VERSION 5.7 ;
  NOWIREEXTENSIONATPIN ON ;
  DIVIDERCHAR "/" ;
  BUSBITCHARS "[]" ;
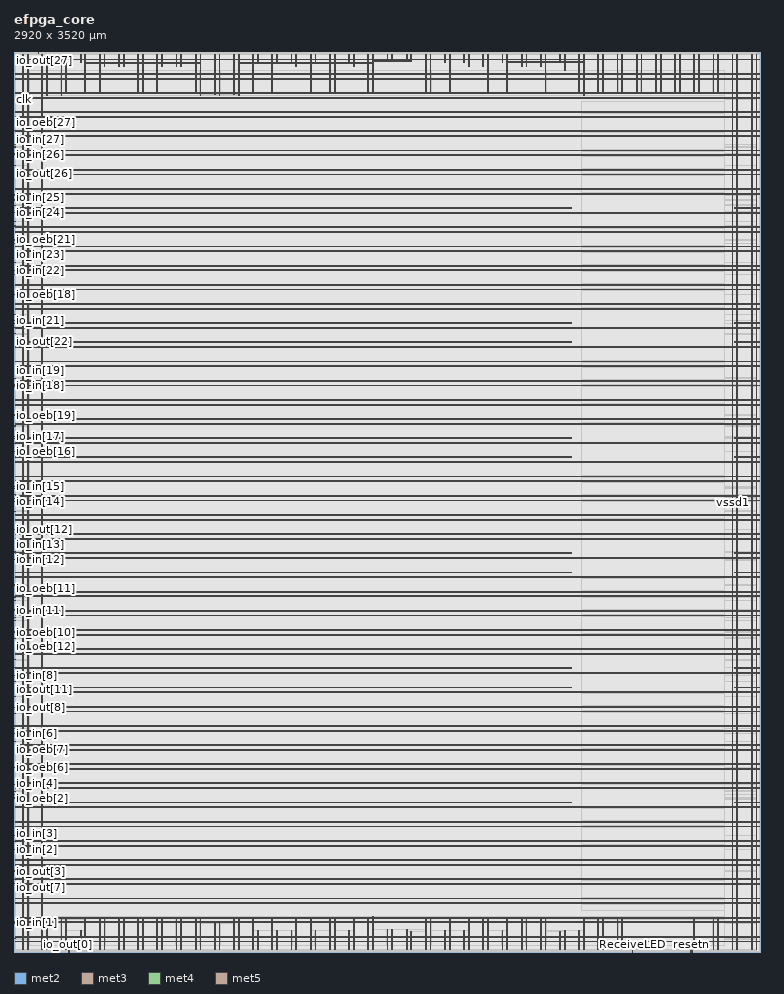
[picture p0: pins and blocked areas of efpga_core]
MACRO efpga_core
  CLASS BLOCK ;
  FOREIGN efpga_core ;
  ORIGIN 0.000 0.000 ;
  SIZE 2920.000 BY 3520.000 ;
  PIN ComActive
    DIRECTION OUTPUT ;
    USE SIGNAL ;
    ANTENNADIFFAREA 2.673000 ;
    PORT
      LAYER met2 ;
        RECT 2646.930 0.000 2647.210 4.000 ;
    END
  END ComActive
  PIN ReceiveLED
    DIRECTION OUTPUT ;
    USE SIGNAL ;
    ANTENNADIFFAREA 2.673000 ;
    PORT
      LAYER met2 ;
        RECT 2418.310 0.000 2418.590 4.000 ;
    END
  END ReceiveLED
  PIN Rx
    DIRECTION INPUT ;
    USE SIGNAL ;
    ANTENNAGATEAREA 0.196500 ;
    PORT
      LAYER met2 ;
        RECT 2653.370 0.000 2653.650 4.000 ;
    END
  END Rx
  PIN clk
    DIRECTION INPUT ;
    USE SIGNAL ;
    ANTENNAGATEAREA 0.213000 ;
    PORT
      LAYER met3 ;
        RECT 0.000 3335.440 4.000 3336.040 ;
    END
  END clk
  PIN io_in[0]
    DIRECTION INPUT ;
    USE SIGNAL ;
    ANTENNAGATEAREA 0.213000 ;
    PORT
      LAYER met3 ;
        RECT 0.000 112.240 4.000 112.840 ;
    END
  END io_in[0]
  PIN io_in[10]
    DIRECTION INPUT ;
    USE SIGNAL ;
    ANTENNAGATEAREA 0.126000 ;
    PORT
      LAYER met3 ;
        RECT 0.000 1309.040 4.000 1309.640 ;
    END
  END io_in[10]
  PIN io_in[11]
    DIRECTION INPUT ;
    USE SIGNAL ;
    ANTENNAGATEAREA 0.196500 ;
    PORT
      LAYER met3 ;
        RECT 0.000 1336.240 4.000 1336.840 ;
    END
  END io_in[11]
  PIN io_in[12]
    DIRECTION INPUT ;
    USE SIGNAL ;
    ANTENNAGATEAREA 0.126000 ;
    PORT
      LAYER met3 ;
        RECT 0.000 1533.440 4.000 1534.040 ;
    END
  END io_in[12]
  PIN io_in[13]
    DIRECTION INPUT ;
    USE SIGNAL ;
    ANTENNAGATEAREA 0.196500 ;
    PORT
      LAYER met3 ;
        RECT 0.000 1564.040 4.000 1564.640 ;
    END
  END io_in[13]
  PIN io_in[14]
    DIRECTION INPUT ;
    USE SIGNAL ;
    ANTENNAGATEAREA 0.126000 ;
    PORT
      LAYER met3 ;
        RECT 0.000 1761.240 4.000 1761.840 ;
    END
  END io_in[14]
  PIN io_in[15]
    DIRECTION INPUT ;
    USE SIGNAL ;
    ANTENNAGATEAREA 0.196500 ;
    PORT
      LAYER met3 ;
        RECT 0.000 1788.440 4.000 1789.040 ;
    END
  END io_in[15]
  PIN io_in[16]
    DIRECTION INPUT ;
    USE SIGNAL ;
    ANTENNAGATEAREA 0.126000 ;
    PORT
      LAYER met3 ;
        RECT 0.000 1989.040 4.000 1989.640 ;
    END
  END io_in[16]
  PIN io_in[17]
    DIRECTION INPUT ;
    USE SIGNAL ;
    ANTENNAGATEAREA 0.196500 ;
    PORT
      LAYER met3 ;
        RECT 0.000 2016.240 4.000 2016.840 ;
    END
  END io_in[17]
  PIN io_in[18]
    DIRECTION INPUT ;
    USE SIGNAL ;
    ANTENNAGATEAREA 0.126000 ;
    PORT
      LAYER met3 ;
        RECT 0.000 2213.440 4.000 2214.040 ;
    END
  END io_in[18]
  PIN io_in[19]
    DIRECTION INPUT ;
    USE SIGNAL ;
    ANTENNAGATEAREA 0.196500 ;
    PORT
      LAYER met3 ;
        RECT 0.000 2244.040 4.000 2244.640 ;
    END
  END io_in[19]
  PIN io_in[1]
    DIRECTION INPUT ;
    USE SIGNAL ;
    ANTENNAGATEAREA 0.213000 ;
    PORT
      LAYER met3 ;
        RECT 0.000 115.640 4.000 116.240 ;
    END
  END io_in[1]
  PIN io_in[20]
    DIRECTION INPUT ;
    USE SIGNAL ;
    ANTENNAGATEAREA 0.126000 ;
    PORT
      LAYER met3 ;
        RECT 0.000 2441.240 4.000 2441.840 ;
    END
  END io_in[20]
  PIN io_in[21]
    DIRECTION INPUT ;
    USE SIGNAL ;
    ANTENNAGATEAREA 0.196500 ;
    PORT
      LAYER met3 ;
        RECT 0.000 2468.440 4.000 2469.040 ;
    END
  END io_in[21]
  PIN io_in[22]
    DIRECTION INPUT ;
    USE SIGNAL ;
    ANTENNAGATEAREA 0.126000 ;
    PORT
      LAYER met3 ;
        RECT 0.000 2665.640 4.000 2666.240 ;
    END
  END io_in[22]
  PIN io_in[23]
    DIRECTION INPUT ;
    USE SIGNAL ;
    ANTENNAGATEAREA 0.196500 ;
    PORT
      LAYER met3 ;
        RECT 0.000 2696.240 4.000 2696.840 ;
    END
  END io_in[23]
  PIN io_in[24]
    DIRECTION INPUT ;
    USE SIGNAL ;
    ANTENNAGATEAREA 0.126000 ;
    PORT
      LAYER met3 ;
        RECT 0.000 2893.440 4.000 2894.040 ;
    END
  END io_in[24]
  PIN io_in[25]
    DIRECTION INPUT ;
    USE SIGNAL ;
    ANTENNAGATEAREA 0.196500 ;
    PORT
      LAYER met3 ;
        RECT 0.000 2920.640 4.000 2921.240 ;
    END
  END io_in[25]
  PIN io_in[26]
    DIRECTION INPUT ;
    USE SIGNAL ;
    ANTENNAGATEAREA 0.126000 ;
    PORT
      LAYER met3 ;
        RECT 0.000 3117.840 4.000 3118.440 ;
    END
  END io_in[26]
  PIN io_in[27]
    DIRECTION INPUT ;
    USE SIGNAL ;
    ANTENNAGATEAREA 0.196500 ;
    PORT
      LAYER met3 ;
        RECT 0.000 3148.440 4.000 3149.040 ;
    END
  END io_in[27]
  PIN io_in[2]
    DIRECTION INPUT ;
    USE SIGNAL ;
    ANTENNAGATEAREA 0.126000 ;
    PORT
      LAYER met3 ;
        RECT 0.000 401.240 4.000 401.840 ;
    END
  END io_in[2]
  PIN io_in[3]
    DIRECTION INPUT ;
    USE SIGNAL ;
    ANTENNAGATEAREA 0.196500 ;
    PORT
      LAYER met3 ;
        RECT 0.000 431.840 4.000 432.440 ;
    END
  END io_in[3]
  PIN io_in[4]
    DIRECTION INPUT ;
    USE SIGNAL ;
    ANTENNAGATEAREA 0.126000 ;
    PORT
      LAYER met3 ;
        RECT 0.000 629.040 4.000 629.640 ;
    END
  END io_in[4]
  PIN io_in[5]
    DIRECTION INPUT ;
    USE SIGNAL ;
    ANTENNAGATEAREA 0.196500 ;
    PORT
      LAYER met3 ;
        RECT 0.000 656.240 4.000 656.840 ;
    END
  END io_in[5]
  PIN io_in[6]
    DIRECTION INPUT ;
    USE SIGNAL ;
    ANTENNAGATEAREA 0.126000 ;
    PORT
      LAYER met3 ;
        RECT 0.000 853.440 4.000 854.040 ;
    END
  END io_in[6]
  PIN io_in[7]
    DIRECTION INPUT ;
    USE SIGNAL ;
    ANTENNAGATEAREA 0.196500 ;
    PORT
      LAYER met3 ;
        RECT 0.000 884.040 4.000 884.640 ;
    END
  END io_in[7]
  PIN io_in[8]
    DIRECTION INPUT ;
    USE SIGNAL ;
    ANTENNAGATEAREA 0.126000 ;
    PORT
      LAYER met3 ;
        RECT 0.000 1081.240 4.000 1081.840 ;
    END
  END io_in[8]
  PIN io_in[9]
    DIRECTION INPUT ;
    USE SIGNAL ;
    ANTENNAGATEAREA 0.196500 ;
    PORT
      LAYER met3 ;
        RECT 0.000 1111.840 4.000 1112.440 ;
    END
  END io_in[9]
  PIN io_oeb[0]
    DIRECTION OUTPUT ;
    USE SIGNAL ;
    ANTENNADIFFAREA 2.673000 ;
    PORT
      LAYER met2 ;
        RECT 215.830 0.000 216.110 4.000 ;
    END
  END io_oeb[0]
  PIN io_oeb[10]
    DIRECTION OUTPUT ;
    USE SIGNAL ;
    ANTENNADIFFAREA 2.673000 ;
    PORT
      LAYER met3 ;
        RECT 0.000 1251.240 4.000 1251.840 ;
    END
  END io_oeb[10]
  PIN io_oeb[11]
    DIRECTION OUTPUT ;
    USE SIGNAL ;
    ANTENNADIFFAREA 2.673000 ;
    PORT
      LAYER met3 ;
        RECT 0.000 1390.640 4.000 1391.240 ;
    END
  END io_oeb[11]
  PIN io_oeb[12]
    DIRECTION OUTPUT ;
    USE SIGNAL ;
    ANTENNADIFFAREA 2.673000 ;
    PORT
      LAYER met3 ;
        RECT 0.000 1227.440 4.000 1228.040 ;
    END
  END io_oeb[12]
  PIN io_oeb[13]
    DIRECTION OUTPUT ;
    USE SIGNAL ;
    ANTENNADIFFAREA 2.673000 ;
    PORT
      LAYER met3 ;
        RECT 0.000 1142.440 4.000 1143.040 ;
    END
  END io_oeb[13]
  PIN io_oeb[14]
    DIRECTION OUTPUT ;
    USE SIGNAL ;
    ANTENNADIFFAREA 2.673000 ;
    PORT
      LAYER met3 ;
        RECT 0.000 1723.840 4.000 1724.440 ;
    END
  END io_oeb[14]
  PIN io_oeb[15]
    DIRECTION OUTPUT ;
    USE SIGNAL ;
    ANTENNADIFFAREA 2.673000 ;
    PORT
      LAYER met3 ;
        RECT 0.000 1339.640 4.000 1340.240 ;
    END
  END io_oeb[15]
  PIN io_oeb[16]
    DIRECTION OUTPUT ;
    USE SIGNAL ;
    ANTENNADIFFAREA 2.673000 ;
    PORT
      LAYER met3 ;
        RECT 0.000 1958.440 4.000 1959.040 ;
    END
  END io_oeb[16]
  PIN io_oeb[17]
    DIRECTION OUTPUT ;
    USE SIGNAL ;
    ANTENNADIFFAREA 2.673000 ;
    PORT
      LAYER met3 ;
        RECT 0.000 2009.440 4.000 2010.040 ;
    END
  END io_oeb[17]
  PIN io_oeb[18]
    DIRECTION OUTPUT ;
    USE SIGNAL ;
    ANTENNADIFFAREA 2.673000 ;
    PORT
      LAYER met3 ;
        RECT 0.000 2570.440 4.000 2571.040 ;
    END
  END io_oeb[18]
  PIN io_oeb[19]
    DIRECTION OUTPUT ;
    USE SIGNAL ;
    ANTENNADIFFAREA 2.673000 ;
    PORT
      LAYER met3 ;
        RECT 0.000 2097.840 4.000 2098.440 ;
    END
  END io_oeb[19]
  PIN io_oeb[1]
    DIRECTION OUTPUT ;
    USE SIGNAL ;
    ANTENNADIFFAREA 2.673000 ;
    PORT
      LAYER met3 ;
        RECT 0.000 51.040 4.000 51.640 ;
    END
  END io_oeb[1]
  PIN io_oeb[20]
    DIRECTION OUTPUT ;
    USE SIGNAL ;
    ANTENNADIFFAREA 2.673000 ;
    PORT
      LAYER met3 ;
        RECT 0.000 2648.640 4.000 2649.240 ;
    END
  END io_oeb[20]
  PIN io_oeb[21]
    DIRECTION OUTPUT ;
    USE SIGNAL ;
    ANTENNADIFFAREA 2.673000 ;
    PORT
      LAYER met3 ;
        RECT 0.000 2784.640 4.000 2785.240 ;
    END
  END io_oeb[21]
  PIN io_oeb[22]
    DIRECTION OUTPUT ;
    USE SIGNAL ;
    ANTENNADIFFAREA 2.673000 ;
    PORT
      LAYER met3 ;
        RECT 0.000 2458.240 4.000 2458.840 ;
    END
  END io_oeb[22]
  PIN io_oeb[23]
    DIRECTION OUTPUT ;
    USE SIGNAL ;
    ANTENNADIFFAREA 2.673000 ;
    PORT
      LAYER met3 ;
        RECT 0.000 2771.040 4.000 2771.640 ;
    END
  END io_oeb[23]
  PIN io_oeb[24]
    DIRECTION OUTPUT ;
    USE SIGNAL ;
    ANTENNADIFFAREA 2.673000 ;
    PORT
      LAYER met3 ;
        RECT 0.000 2958.040 4.000 2958.640 ;
    END
  END io_oeb[24]
  PIN io_oeb[25]
    DIRECTION OUTPUT ;
    USE SIGNAL ;
    ANTENNADIFFAREA 2.673000 ;
    PORT
      LAYER met3 ;
        RECT 0.000 2839.040 4.000 2839.640 ;
    END
  END io_oeb[25]
  PIN io_oeb[26]
    DIRECTION OUTPUT ;
    USE SIGNAL ;
    ANTENNADIFFAREA 2.673000 ;
    PORT
      LAYER met3 ;
        RECT 0.000 2856.040 4.000 2856.640 ;
    END
  END io_oeb[26]
  PIN io_oeb[27]
    DIRECTION OUTPUT ;
    USE SIGNAL ;
    ANTENNADIFFAREA 2.673000 ;
    PORT
      LAYER met3 ;
        RECT 0.000 3213.040 4.000 3213.640 ;
    END
  END io_oeb[27]
  PIN io_oeb[2]
    DIRECTION OUTPUT ;
    USE SIGNAL ;
    ANTENNADIFFAREA 2.673000 ;
    PORT
      LAYER met3 ;
        RECT 0.000 598.440 4.000 599.040 ;
    END
  END io_oeb[2]
  PIN io_oeb[3]
    DIRECTION OUTPUT ;
    USE SIGNAL ;
    ANTENNADIFFAREA 2.673000 ;
    PORT
      LAYER met3 ;
        RECT 0.000 615.440 4.000 616.040 ;
    END
  END io_oeb[3]
  PIN io_oeb[4]
    DIRECTION OUTPUT ;
    USE SIGNAL ;
    ANTENNADIFFAREA 2.673000 ;
    PORT
      LAYER met3 ;
        RECT 0.000 268.640 4.000 269.240 ;
    END
  END io_oeb[4]
  PIN io_oeb[5]
    DIRECTION OUTPUT ;
    USE SIGNAL ;
    ANTENNADIFFAREA 2.673000 ;
    PORT
      LAYER met3 ;
        RECT 0.000 1387.240 4.000 1387.840 ;
    END
  END io_oeb[5]
  PIN io_oeb[6]
    DIRECTION OUTPUT ;
    USE SIGNAL ;
    ANTENNADIFFAREA 2.673000 ;
    PORT
      LAYER met3 ;
        RECT 0.000 720.840 4.000 721.440 ;
    END
  END io_oeb[6]
  PIN io_oeb[7]
    DIRECTION OUTPUT ;
    USE SIGNAL ;
    ANTENNADIFFAREA 2.673000 ;
    PORT
      LAYER met3 ;
        RECT 0.000 822.840 4.000 823.440 ;
    END
  END io_oeb[7]
  PIN io_oeb[8]
    DIRECTION OUTPUT ;
    USE SIGNAL ;
    ANTENNADIFFAREA 2.673000 ;
    PORT
      LAYER met3 ;
        RECT 0.000 999.640 4.000 1000.240 ;
    END
  END io_oeb[8]
  PIN io_oeb[9]
    DIRECTION OUTPUT ;
    USE SIGNAL ;
    ANTENNADIFFAREA 2.673000 ;
    PORT
      LAYER met3 ;
        RECT 0.000 880.640 4.000 881.240 ;
    END
  END io_oeb[9]
  PIN io_out[0]
    DIRECTION OUTPUT ;
    USE SIGNAL ;
    ANTENNADIFFAREA 2.673000 ;
    PORT
      LAYER met2 ;
        RECT 212.610 0.000 212.890 4.000 ;
    END
  END io_out[0]
  PIN io_out[10]
    DIRECTION OUTPUT ;
    USE SIGNAL ;
    ANTENNADIFFAREA 2.673000 ;
    PORT
      LAYER met3 ;
        RECT 0.000 1295.440 4.000 1296.040 ;
    END
  END io_out[10]
  PIN io_out[11]
    DIRECTION OUTPUT ;
    USE SIGNAL ;
    ANTENNADIFFAREA 2.673000 ;
    PORT
      LAYER met3 ;
        RECT 0.000 1057.440 4.000 1058.040 ;
    END
  END io_out[11]
  PIN io_out[12]
    DIRECTION OUTPUT ;
    USE SIGNAL ;
    ANTENNADIFFAREA 2.673000 ;
    PORT
      LAYER met3 ;
        RECT 0.000 1652.440 4.000 1653.040 ;
    END
  END io_out[12]
  PIN io_out[13]
    DIRECTION OUTPUT ;
    USE SIGNAL ;
    ANTENNADIFFAREA 2.673000 ;
    PORT
      LAYER met3 ;
        RECT 0.000 1819.040 4.000 1819.640 ;
    END
  END io_out[13]
  PIN io_out[14]
    DIRECTION OUTPUT ;
    USE SIGNAL ;
    ANTENNADIFFAREA 2.673000 ;
    PORT
      LAYER met3 ;
        RECT 0.000 1373.640 4.000 1374.240 ;
    END
  END io_out[14]
  PIN io_out[15]
    DIRECTION OUTPUT ;
    USE SIGNAL ;
    ANTENNADIFFAREA 2.673000 ;
    PORT
      LAYER met3 ;
        RECT 0.000 1812.240 4.000 1812.840 ;
    END
  END io_out[15]
  PIN io_out[16]
    DIRECTION OUTPUT ;
    USE SIGNAL ;
    ANTENNADIFFAREA 2.673000 ;
    PORT
      LAYER met3 ;
        RECT 0.000 2220.240 4.000 2220.840 ;
    END
  END io_out[16]
  PIN io_out[17]
    DIRECTION OUTPUT ;
    USE SIGNAL ;
    ANTENNADIFFAREA 2.673000 ;
    PORT
      LAYER met3 ;
        RECT 0.000 1774.840 4.000 1775.440 ;
    END
  END io_out[17]
  PIN io_out[18]
    DIRECTION OUTPUT ;
    USE SIGNAL ;
    ANTENNADIFFAREA 2.673000 ;
    PORT
      LAYER met3 ;
        RECT 0.000 2057.040 4.000 2057.640 ;
    END
  END io_out[18]
  PIN io_out[19]
    DIRECTION OUTPUT ;
    USE SIGNAL ;
    ANTENNADIFFAREA 2.673000 ;
    PORT
      LAYER met3 ;
        RECT 0.000 2101.240 4.000 2101.840 ;
    END
  END io_out[19]
  PIN io_out[1]
    DIRECTION OUTPUT ;
    USE SIGNAL ;
    ANTENNADIFFAREA 2.673000 ;
    PORT
      LAYER met3 ;
        RECT 0.000 119.040 4.000 119.640 ;
    END
  END io_out[1]
  PIN io_out[20]
    DIRECTION OUTPUT ;
    USE SIGNAL ;
    ANTENNADIFFAREA 2.673000 ;
    PORT
      LAYER met3 ;
        RECT 0.000 2941.040 4.000 2941.640 ;
    END
  END io_out[20]
  PIN io_out[21]
    DIRECTION OUTPUT ;
    USE SIGNAL ;
    ANTENNADIFFAREA 2.673000 ;
    PORT
      LAYER met3 ;
        RECT 0.000 2492.240 4.000 2492.840 ;
    END
  END io_out[21]
  PIN io_out[22]
    DIRECTION OUTPUT ;
    USE SIGNAL ;
    ANTENNADIFFAREA 2.673000 ;
    PORT
      LAYER met3 ;
        RECT 0.000 2417.440 4.000 2418.040 ;
    END
  END io_out[22]
  PIN io_out[23]
    DIRECTION OUTPUT ;
    USE SIGNAL ;
    ANTENNADIFFAREA 2.673000 ;
    PORT
      LAYER met3 ;
        RECT 0.000 3121.240 4.000 3121.840 ;
    END
  END io_out[23]
  PIN io_out[24]
    DIRECTION OUTPUT ;
    USE SIGNAL ;
    ANTENNADIFFAREA 2.673000 ;
    PORT
      LAYER met3 ;
        RECT 0.000 2961.440 4.000 2962.040 ;
    END
  END io_out[24]
  PIN io_out[25]
    DIRECTION OUTPUT ;
    USE SIGNAL ;
    ANTENNADIFFAREA 2.673000 ;
    PORT
      LAYER met3 ;
        RECT 0.000 3158.640 4.000 3159.240 ;
    END
  END io_out[25]
  PIN io_out[26]
    DIRECTION OUTPUT ;
    USE SIGNAL ;
    ANTENNADIFFAREA 2.673000 ;
    PORT
      LAYER met3 ;
        RECT 0.000 3077.040 4.000 3077.640 ;
    END
  END io_out[26]
  PIN io_out[27]
    DIRECTION OUTPUT ;
    USE SIGNAL ;
    ANTENNADIFFAREA 2.673000 ;
    PORT
      LAYER met2 ;
        RECT 96.690 3516.000 96.970 3520.000 ;
    END
  END io_out[27]
  PIN io_out[2]
    DIRECTION OUTPUT ;
    USE SIGNAL ;
    ANTENNADIFFAREA 2.673000 ;
    PORT
      LAYER met3 ;
        RECT 0.000 455.640 4.000 456.240 ;
    END
  END io_out[2]
  PIN io_out[3]
    DIRECTION OUTPUT ;
    USE SIGNAL ;
    ANTENNADIFFAREA 2.673000 ;
    PORT
      LAYER met3 ;
        RECT 0.000 316.240 4.000 316.840 ;
    END
  END io_out[3]
  PIN io_out[4]
    DIRECTION OUTPUT ;
    USE SIGNAL ;
    ANTENNADIFFAREA 2.673000 ;
    PORT
      LAYER met3 ;
        RECT 0.000 1434.840 4.000 1435.440 ;
    END
  END io_out[4]
  PIN io_out[5]
    DIRECTION OUTPUT ;
    USE SIGNAL ;
    ANTENNADIFFAREA 2.673000 ;
    PORT
      LAYER met3 ;
        RECT 0.000 601.840 4.000 602.440 ;
    END
  END io_out[5]
  PIN io_out[6]
    DIRECTION OUTPUT ;
    USE SIGNAL ;
    ANTENNADIFFAREA 2.673000 ;
    PORT
      LAYER met3 ;
        RECT 0.000 873.840 4.000 874.440 ;
    END
  END io_out[6]
  PIN io_out[7]
    DIRECTION OUTPUT ;
    USE SIGNAL ;
    ANTENNADIFFAREA 2.673000 ;
    PORT
      LAYER met3 ;
        RECT 0.000 282.240 4.000 282.840 ;
    END
  END io_out[7]
  PIN io_out[8]
    DIRECTION OUTPUT ;
    USE SIGNAL ;
    ANTENNADIFFAREA 2.673000 ;
    PORT
      LAYER met3 ;
        RECT 0.000 955.440 4.000 956.040 ;
    END
  END io_out[8]
  PIN io_out[9]
    DIRECTION OUTPUT ;
    USE SIGNAL ;
    ANTENNADIFFAREA 2.673000 ;
    PORT
      LAYER met3 ;
        RECT 0.000 931.640 4.000 932.240 ;
    END
  END io_out[9]
  PIN resetn
    DIRECTION INPUT ;
    USE SIGNAL ;
    ANTENNAGATEAREA 0.196500 ;
    PORT
      LAYER met2 ;
        RECT 2650.150 0.000 2650.430 4.000 ;
    END
  END resetn
  PIN vccd1
    DIRECTION INOUT ;
    USE POWER ;
    PORT
      LAYER met4 ;
        RECT 52.570 10.640 55.670 3509.040 ;
    END
    PORT
      LAYER met4 ;
        RECT 127.570 10.640 130.670 127.395 ;
    END
    PORT
      LAYER met4 ;
        RECT 127.570 3350.425 130.670 3509.040 ;
    END
    PORT
      LAYER met4 ;
        RECT 202.570 10.640 205.670 126.000 ;
    END
    PORT
      LAYER met4 ;
        RECT 202.570 3357.905 205.670 3509.040 ;
    END
    PORT
      LAYER met4 ;
        RECT 277.570 10.640 280.670 131.275 ;
    END
    PORT
      LAYER met4 ;
        RECT 277.570 3357.905 280.670 3509.040 ;
    END
    PORT
      LAYER met4 ;
        RECT 352.570 10.640 355.670 131.275 ;
    END
    PORT
      LAYER met4 ;
        RECT 352.570 3465.065 355.670 3509.040 ;
    END
    PORT
      LAYER met4 ;
        RECT 427.570 10.640 430.670 131.275 ;
    END
    PORT
      LAYER met4 ;
        RECT 427.570 3465.065 430.670 3509.040 ;
    END
    PORT
      LAYER met4 ;
        RECT 502.570 10.640 505.670 131.275 ;
    END
    PORT
      LAYER met4 ;
        RECT 502.570 3357.905 505.670 3509.040 ;
    END
    PORT
      LAYER met4 ;
        RECT 577.570 10.640 580.670 131.275 ;
    END
    PORT
      LAYER met4 ;
        RECT 577.570 3465.065 580.670 3509.040 ;
    END
    PORT
      LAYER met4 ;
        RECT 652.570 10.640 655.670 131.275 ;
    END
    PORT
      LAYER met4 ;
        RECT 652.570 3465.065 655.670 3509.040 ;
    END
    PORT
      LAYER met4 ;
        RECT 727.570 10.640 730.670 135.355 ;
    END
    PORT
      LAYER met4 ;
        RECT 727.570 3351.105 730.670 3509.040 ;
    END
    PORT
      LAYER met4 ;
        RECT 802.570 10.640 805.670 110.135 ;
    END
    PORT
      LAYER met4 ;
        RECT 802.570 3351.105 805.670 3509.040 ;
    END
    PORT
      LAYER met4 ;
        RECT 877.570 10.640 880.670 135.355 ;
    END
    PORT
      LAYER met4 ;
        RECT 877.570 3351.105 880.670 3509.040 ;
    END
    PORT
      LAYER met4 ;
        RECT 952.570 10.640 955.670 84.940 ;
    END
    PORT
      LAYER met4 ;
        RECT 952.570 3478.020 955.670 3509.040 ;
    END
    PORT
      LAYER met4 ;
        RECT 1027.570 10.640 1030.670 84.940 ;
    END
    PORT
      LAYER met4 ;
        RECT 1027.570 3478.020 1030.670 3509.040 ;
    END
    PORT
      LAYER met4 ;
        RECT 1102.570 10.640 1105.670 131.275 ;
    END
    PORT
      LAYER met4 ;
        RECT 1102.570 3465.065 1105.670 3509.040 ;
    END
    PORT
      LAYER met4 ;
        RECT 1177.570 10.640 1180.670 84.940 ;
    END
    PORT
      LAYER met4 ;
        RECT 1177.570 3478.020 1180.670 3509.040 ;
    END
    PORT
      LAYER met4 ;
        RECT 1252.570 10.640 1255.670 131.275 ;
    END
    PORT
      LAYER met4 ;
        RECT 1252.570 3357.905 1255.670 3509.040 ;
    END
    PORT
      LAYER met4 ;
        RECT 1327.570 10.640 1330.670 131.275 ;
    END
    PORT
      LAYER met4 ;
        RECT 1327.570 3465.065 1330.670 3509.040 ;
    END
    PORT
      LAYER met4 ;
        RECT 1402.570 10.640 1405.670 137.395 ;
    END
    PORT
      LAYER met4 ;
        RECT 1402.570 3363.765 1405.670 3509.040 ;
    END
    PORT
      LAYER met4 ;
        RECT 1477.570 10.640 1480.670 89.055 ;
    END
    PORT
      LAYER met4 ;
        RECT 1477.570 3482.065 1480.670 3509.040 ;
    END
    PORT
      LAYER met4 ;
        RECT 1552.570 10.640 1555.670 79.500 ;
    END
    PORT
      LAYER met4 ;
        RECT 1552.570 3483.460 1555.670 3509.040 ;
    END
    PORT
      LAYER met4 ;
        RECT 1627.570 10.640 1630.670 131.275 ;
    END
    PORT
      LAYER met4 ;
        RECT 1627.570 3363.765 1630.670 3509.040 ;
    END
    PORT
      LAYER met4 ;
        RECT 1702.570 10.640 1705.670 131.275 ;
    END
    PORT
      LAYER met4 ;
        RECT 1702.570 3357.905 1705.670 3509.040 ;
    END
    PORT
      LAYER met4 ;
        RECT 1777.570 10.640 1780.670 131.275 ;
    END
    PORT
      LAYER met4 ;
        RECT 1777.570 3465.065 1780.670 3509.040 ;
    END
    PORT
      LAYER met4 ;
        RECT 1852.570 10.640 1855.670 131.275 ;
    END
    PORT
      LAYER met4 ;
        RECT 1852.570 3357.905 1855.670 3509.040 ;
    END
    PORT
      LAYER met4 ;
        RECT 1927.570 10.640 1930.670 131.275 ;
    END
    PORT
      LAYER met4 ;
        RECT 1927.570 3357.905 1930.670 3509.040 ;
    END
    PORT
      LAYER met4 ;
        RECT 2002.570 10.640 2005.670 131.275 ;
    END
    PORT
      LAYER met4 ;
        RECT 2002.570 3465.065 2005.670 3509.040 ;
    END
    PORT
      LAYER met4 ;
        RECT 2077.570 10.640 2080.670 131.275 ;
    END
    PORT
      LAYER met4 ;
        RECT 2077.570 3359.265 2080.670 3509.040 ;
    END
    PORT
      LAYER met4 ;
        RECT 2152.570 10.640 2155.670 83.615 ;
    END
    PORT
      LAYER met4 ;
        RECT 2152.570 3448.065 2155.670 3509.040 ;
    END
    PORT
      LAYER met4 ;
        RECT 2227.570 10.640 2230.670 133.315 ;
    END
    PORT
      LAYER met4 ;
        RECT 2227.570 3350.845 2230.670 3509.040 ;
    END
    PORT
      LAYER met4 ;
        RECT 2302.570 10.640 2305.670 125.340 ;
    END
    PORT
      LAYER met4 ;
        RECT 2302.570 3363.580 2305.670 3509.040 ;
    END
    PORT
      LAYER met4 ;
        RECT 2377.570 10.640 2380.670 125.340 ;
    END
    PORT
      LAYER met4 ;
        RECT 2377.570 3363.580 2380.670 3509.040 ;
    END
    PORT
      LAYER met4 ;
        RECT 2452.570 3363.580 2455.670 3509.040 ;
    END
    PORT
      LAYER met4 ;
        RECT 2527.570 3363.580 2530.670 3509.040 ;
    END
    PORT
      LAYER met4 ;
        RECT 2602.570 3363.580 2605.670 3509.040 ;
    END
    PORT
      LAYER met4 ;
        RECT 2677.570 3363.580 2680.670 3509.040 ;
    END
    PORT
      LAYER met4 ;
        RECT 2752.570 10.640 2755.670 125.340 ;
    END
    PORT
      LAYER met4 ;
        RECT 2752.570 3363.580 2755.670 3509.040 ;
    END
    PORT
      LAYER met4 ;
        RECT 2827.570 10.640 2830.670 3509.040 ;
    END
    PORT
      LAYER met4 ;
        RECT 2902.570 10.640 2905.670 3509.040 ;
    END
    PORT
      LAYER met5 ;
        RECT 5.280 57.930 2914.340 61.030 ;
    END
    PORT
      LAYER met5 ;
        RECT 5.280 132.930 2914.340 136.030 ;
    END
    PORT
      LAYER met5 ;
        RECT 5.280 207.930 2914.340 211.030 ;
    END
    PORT
      LAYER met5 ;
        RECT 5.280 282.930 2914.340 286.030 ;
    END
    PORT
      LAYER met5 ;
        RECT 5.280 357.930 2914.340 361.030 ;
    END
    PORT
      LAYER met5 ;
        RECT 5.280 432.930 2914.340 436.030 ;
    END
    PORT
      LAYER met5 ;
        RECT 5.280 507.930 2914.340 511.030 ;
    END
    PORT
      LAYER met5 ;
        RECT 5.280 582.930 2179.420 586.030 ;
    END
    PORT
      LAYER met5 ;
        RECT 5.280 657.930 2914.340 661.030 ;
    END
    PORT
      LAYER met5 ;
        RECT 5.280 732.930 2914.340 736.030 ;
    END
    PORT
      LAYER met5 ;
        RECT 5.280 807.930 2914.340 811.030 ;
    END
    PORT
      LAYER met5 ;
        RECT 5.280 882.930 2914.340 886.030 ;
    END
    PORT
      LAYER met5 ;
        RECT 5.280 957.930 2914.340 961.030 ;
    END
    PORT
      LAYER met5 ;
        RECT 5.280 1032.930 2179.420 1036.030 ;
    END
    PORT
      LAYER met5 ;
        RECT 5.280 1107.930 2179.420 1111.030 ;
    END
    PORT
      LAYER met5 ;
        RECT 5.280 1182.930 2914.340 1186.030 ;
    END
    PORT
      LAYER met5 ;
        RECT 5.280 1257.930 2914.340 1261.030 ;
    END
    PORT
      LAYER met5 ;
        RECT 5.280 1332.930 2914.340 1336.030 ;
    END
    PORT
      LAYER met5 ;
        RECT 5.280 1407.930 2914.340 1411.030 ;
    END
    PORT
      LAYER met5 ;
        RECT 5.280 1482.930 2179.420 1486.030 ;
    END
    PORT
      LAYER met5 ;
        RECT 5.280 1557.930 2179.420 1561.030 ;
    END
    PORT
      LAYER met5 ;
        RECT 5.280 1632.930 2914.340 1636.030 ;
    END
    PORT
      LAYER met5 ;
        RECT 5.280 1707.930 2914.340 1711.030 ;
    END
    PORT
      LAYER met5 ;
        RECT 5.280 1782.930 2914.340 1786.030 ;
    END
    PORT
      LAYER met5 ;
        RECT 5.280 1857.930 2914.340 1861.030 ;
    END
    PORT
      LAYER met5 ;
        RECT 5.280 1932.930 2179.420 1936.030 ;
    END
    PORT
      LAYER met5 ;
        RECT 5.280 2007.930 2179.420 2011.030 ;
    END
    PORT
      LAYER met5 ;
        RECT 5.280 2082.930 2914.340 2086.030 ;
    END
    PORT
      LAYER met5 ;
        RECT 5.280 2157.930 2914.340 2161.030 ;
    END
    PORT
      LAYER met5 ;
        RECT 5.280 2232.930 2914.340 2236.030 ;
    END
    PORT
      LAYER met5 ;
        RECT 5.280 2307.930 2914.340 2311.030 ;
    END
    PORT
      LAYER met5 ;
        RECT 5.280 2382.930 2179.420 2386.030 ;
    END
    PORT
      LAYER met5 ;
        RECT 5.280 2457.930 2179.420 2461.030 ;
    END
    PORT
      LAYER met5 ;
        RECT 5.280 2532.930 2914.340 2536.030 ;
    END
    PORT
      LAYER met5 ;
        RECT 5.280 2607.930 2914.340 2611.030 ;
    END
    PORT
      LAYER met5 ;
        RECT 5.280 2682.930 2914.340 2686.030 ;
    END
    PORT
      LAYER met5 ;
        RECT 5.280 2757.930 2914.340 2761.030 ;
    END
    PORT
      LAYER met5 ;
        RECT 5.280 2832.930 2914.340 2836.030 ;
    END
    PORT
      LAYER met5 ;
        RECT 5.280 2907.930 2179.420 2911.030 ;
    END
    PORT
      LAYER met5 ;
        RECT 5.280 2982.930 2914.340 2986.030 ;
    END
    PORT
      LAYER met5 ;
        RECT 5.280 3057.930 2914.340 3061.030 ;
    END
    PORT
      LAYER met5 ;
        RECT 5.280 3132.930 2914.340 3136.030 ;
    END
    PORT
      LAYER met5 ;
        RECT 5.280 3207.930 2914.340 3211.030 ;
    END
    PORT
      LAYER met5 ;
        RECT 5.280 3282.930 2914.340 3286.030 ;
    END
    PORT
      LAYER met5 ;
        RECT 5.280 3357.930 2914.340 3361.030 ;
    END
    PORT
      LAYER met5 ;
        RECT 5.280 3432.930 2914.340 3436.030 ;
    END
    PORT
      LAYER met5 ;
        RECT 2816.280 582.930 2914.340 586.030 ;
    END
    PORT
      LAYER met5 ;
        RECT 2816.280 1032.930 2914.340 1036.030 ;
    END
    PORT
      LAYER met5 ;
        RECT 2816.280 1107.930 2914.340 1111.030 ;
    END
    PORT
      LAYER met5 ;
        RECT 2816.280 1482.930 2914.340 1486.030 ;
    END
    PORT
      LAYER met5 ;
        RECT 2816.280 1557.930 2914.340 1561.030 ;
    END
    PORT
      LAYER met5 ;
        RECT 2816.280 1932.930 2914.340 1936.030 ;
    END
    PORT
      LAYER met5 ;
        RECT 2816.280 2007.930 2914.340 2011.030 ;
    END
    PORT
      LAYER met5 ;
        RECT 2816.280 2382.930 2914.340 2386.030 ;
    END
    PORT
      LAYER met5 ;
        RECT 2816.280 2457.930 2914.340 2461.030 ;
    END
    PORT
      LAYER met5 ;
        RECT 2816.280 2907.930 2914.340 2911.030 ;
    END
    PORT
      LAYER met5 ;
        RECT 277.570 3474.950 730.670 3478.050 ;
    END
    PORT
      LAYER met5 ;
        RECT 877.570 3474.950 1405.670 3478.050 ;
    END
    PORT
      LAYER met5 ;
        RECT 1402.570 3481.750 1555.670 3484.850 ;
    END
    PORT
      LAYER met5 ;
        RECT 1927.570 3478.350 2230.670 3481.450 ;
    END
  END vccd1
  PIN vssd1
    DIRECTION INOUT ;
    USE GROUND ;
    PORT
      LAYER met4 ;
        RECT 33.970 10.640 37.070 3509.040 ;
    END
    PORT
      LAYER met4 ;
        RECT 108.970 10.640 112.070 3509.040 ;
    END
    PORT
      LAYER met4 ;
        RECT 183.970 10.640 187.070 127.395 ;
    END
    PORT
      LAYER met4 ;
        RECT 183.970 3350.425 187.070 3509.040 ;
    END
    PORT
      LAYER met4 ;
        RECT 258.970 10.640 262.070 84.940 ;
    END
    PORT
      LAYER met4 ;
        RECT 258.970 3478.020 262.070 3509.040 ;
    END
    PORT
      LAYER met4 ;
        RECT 333.970 10.640 337.070 131.275 ;
    END
    PORT
      LAYER met4 ;
        RECT 333.970 3357.905 337.070 3509.040 ;
    END
    PORT
      LAYER met4 ;
        RECT 408.970 10.640 412.070 131.275 ;
    END
    PORT
      LAYER met4 ;
        RECT 408.970 3465.065 412.070 3509.040 ;
    END
    PORT
      LAYER met4 ;
        RECT 483.970 10.640 487.070 131.275 ;
    END
    PORT
      LAYER met4 ;
        RECT 483.970 3357.905 487.070 3509.040 ;
    END
    PORT
      LAYER met4 ;
        RECT 558.970 10.640 562.070 131.275 ;
    END
    PORT
      LAYER met4 ;
        RECT 558.970 3357.905 562.070 3509.040 ;
    END
    PORT
      LAYER met4 ;
        RECT 633.970 10.640 637.070 131.275 ;
    END
    PORT
      LAYER met4 ;
        RECT 633.970 3465.065 637.070 3509.040 ;
    END
    PORT
      LAYER met4 ;
        RECT 708.970 10.640 712.070 131.275 ;
    END
    PORT
      LAYER met4 ;
        RECT 708.970 3357.905 712.070 3509.040 ;
    END
    PORT
      LAYER met4 ;
        RECT 783.970 10.640 787.070 110.135 ;
    END
    PORT
      LAYER met4 ;
        RECT 783.970 3354.540 787.070 3509.040 ;
    END
    PORT
      LAYER met4 ;
        RECT 858.970 10.640 862.070 135.355 ;
    END
    PORT
      LAYER met4 ;
        RECT 858.970 3354.540 862.070 3509.040 ;
    END
    PORT
      LAYER met4 ;
        RECT 933.970 10.640 937.070 131.275 ;
    END
    PORT
      LAYER met4 ;
        RECT 933.970 3357.905 937.070 3509.040 ;
    END
    PORT
      LAYER met4 ;
        RECT 1008.970 10.640 1012.070 131.275 ;
    END
    PORT
      LAYER met4 ;
        RECT 1008.970 3357.905 1012.070 3509.040 ;
    END
    PORT
      LAYER met4 ;
        RECT 1083.970 10.640 1087.070 84.940 ;
    END
    PORT
      LAYER met4 ;
        RECT 1083.970 3478.020 1087.070 3509.040 ;
    END
    PORT
      LAYER met4 ;
        RECT 1158.970 10.640 1162.070 131.275 ;
    END
    PORT
      LAYER met4 ;
        RECT 1158.970 3357.905 1162.070 3509.040 ;
    END
    PORT
      LAYER met4 ;
        RECT 1233.970 10.640 1237.070 131.275 ;
    END
    PORT
      LAYER met4 ;
        RECT 1233.970 3357.905 1237.070 3509.040 ;
    END
    PORT
      LAYER met4 ;
        RECT 1308.970 10.640 1312.070 84.940 ;
    END
    PORT
      LAYER met4 ;
        RECT 1308.970 3478.020 1312.070 3509.040 ;
    END
    PORT
      LAYER met4 ;
        RECT 1383.970 10.640 1387.070 131.275 ;
    END
    PORT
      LAYER met4 ;
        RECT 1383.970 3363.765 1387.070 3509.040 ;
    END
    PORT
      LAYER met4 ;
        RECT 1458.970 10.640 1462.070 89.055 ;
    END
    PORT
      LAYER met4 ;
        RECT 1458.970 3482.065 1462.070 3509.040 ;
    END
    PORT
      LAYER met4 ;
        RECT 1533.970 10.640 1537.070 89.055 ;
    END
    PORT
      LAYER met4 ;
        RECT 1533.970 3482.065 1537.070 3509.040 ;
    END
    PORT
      LAYER met4 ;
        RECT 1608.970 10.640 1612.070 131.275 ;
    END
    PORT
      LAYER met4 ;
        RECT 1608.970 3363.765 1612.070 3509.040 ;
    END
    PORT
      LAYER met4 ;
        RECT 1683.970 10.640 1687.070 84.940 ;
    END
    PORT
      LAYER met4 ;
        RECT 1683.970 3478.020 1687.070 3509.040 ;
    END
    PORT
      LAYER met4 ;
        RECT 1758.970 10.640 1762.070 84.940 ;
    END
    PORT
      LAYER met4 ;
        RECT 1758.970 3478.020 1762.070 3509.040 ;
    END
    PORT
      LAYER met4 ;
        RECT 1833.970 10.640 1837.070 131.275 ;
    END
    PORT
      LAYER met4 ;
        RECT 1833.970 3465.065 1837.070 3509.040 ;
    END
    PORT
      LAYER met4 ;
        RECT 1908.970 10.640 1912.070 84.940 ;
    END
    PORT
      LAYER met4 ;
        RECT 1908.970 3478.020 1912.070 3509.040 ;
    END
    PORT
      LAYER met4 ;
        RECT 1983.970 10.640 1987.070 131.275 ;
    END
    PORT
      LAYER met4 ;
        RECT 1983.970 3465.065 1987.070 3509.040 ;
    END
    PORT
      LAYER met4 ;
        RECT 2058.970 10.640 2062.070 131.275 ;
    END
    PORT
      LAYER met4 ;
        RECT 2058.970 3465.065 2062.070 3509.040 ;
    END
    PORT
      LAYER met4 ;
        RECT 2133.970 10.640 2137.070 79.500 ;
    END
    PORT
      LAYER met4 ;
        RECT 2133.970 3483.460 2137.070 3509.040 ;
    END
    PORT
      LAYER met4 ;
        RECT 2208.970 10.640 2212.070 83.615 ;
    END
    PORT
      LAYER met4 ;
        RECT 2208.970 3359.265 2212.070 3509.040 ;
    END
    PORT
      LAYER met4 ;
        RECT 2283.970 10.640 2287.070 125.360 ;
    END
    PORT
      LAYER met4 ;
        RECT 2283.970 3363.580 2287.070 3509.040 ;
    END
    PORT
      LAYER met4 ;
        RECT 2358.970 10.640 2362.070 125.360 ;
    END
    PORT
      LAYER met4 ;
        RECT 2358.970 3363.580 2362.070 3509.040 ;
    END
    PORT
      LAYER met4 ;
        RECT 2433.970 3363.580 2437.070 3509.040 ;
    END
    PORT
      LAYER met4 ;
        RECT 2508.970 3363.580 2512.070 3509.040 ;
    END
    PORT
      LAYER met4 ;
        RECT 2583.970 3363.580 2587.070 3509.040 ;
    END
    PORT
      LAYER met4 ;
        RECT 2658.970 10.640 2662.070 125.340 ;
    END
    PORT
      LAYER met4 ;
        RECT 2658.970 3363.580 2662.070 3509.040 ;
    END
    PORT
      LAYER met4 ;
        RECT 2733.970 10.640 2737.070 125.360 ;
    END
    PORT
      LAYER met4 ;
        RECT 2733.970 3363.580 2737.070 3509.040 ;
    END
    PORT
      LAYER met4 ;
        RECT 2808.970 10.640 2812.070 3509.040 ;
    END
    PORT
      LAYER met4 ;
        RECT 2883.970 10.640 2887.070 3509.040 ;
    END
    PORT
      LAYER met5 ;
        RECT 5.280 39.330 2914.340 42.430 ;
    END
    PORT
      LAYER met5 ;
        RECT 5.280 114.330 2914.340 117.430 ;
    END
    PORT
      LAYER met5 ;
        RECT 5.280 189.330 2914.340 192.430 ;
    END
    PORT
      LAYER met5 ;
        RECT 5.280 264.330 2914.340 267.430 ;
    END
    PORT
      LAYER met5 ;
        RECT 5.280 339.330 2914.340 342.430 ;
    END
    PORT
      LAYER met5 ;
        RECT 5.280 414.330 2914.340 417.430 ;
    END
    PORT
      LAYER met5 ;
        RECT 5.280 489.330 2914.340 492.430 ;
    END
    PORT
      LAYER met5 ;
        RECT 5.280 564.330 2914.340 567.430 ;
    END
    PORT
      LAYER met5 ;
        RECT 5.280 639.330 2914.340 642.430 ;
    END
    PORT
      LAYER met5 ;
        RECT 5.280 714.330 2914.340 717.430 ;
    END
    PORT
      LAYER met5 ;
        RECT 5.280 789.330 2914.340 792.430 ;
    END
    PORT
      LAYER met5 ;
        RECT 5.280 864.330 2914.340 867.430 ;
    END
    PORT
      LAYER met5 ;
        RECT 5.280 939.330 2914.340 942.430 ;
    END
    PORT
      LAYER met5 ;
        RECT 5.280 1014.330 2914.340 1017.430 ;
    END
    PORT
      LAYER met5 ;
        RECT 5.280 1089.330 2914.340 1092.430 ;
    END
    PORT
      LAYER met5 ;
        RECT 5.280 1164.330 2914.340 1167.430 ;
    END
    PORT
      LAYER met5 ;
        RECT 5.280 1239.330 2914.340 1242.430 ;
    END
    PORT
      LAYER met5 ;
        RECT 5.280 1314.330 2914.340 1317.430 ;
    END
    PORT
      LAYER met5 ;
        RECT 5.280 1389.330 2914.340 1392.430 ;
    END
    PORT
      LAYER met5 ;
        RECT 5.280 1464.330 2914.340 1467.430 ;
    END
    PORT
      LAYER met5 ;
        RECT 5.280 1539.330 2914.340 1542.430 ;
    END
    PORT
      LAYER met5 ;
        RECT 5.280 1614.330 2914.340 1617.430 ;
    END
    PORT
      LAYER met5 ;
        RECT 5.280 1689.330 2914.340 1692.430 ;
    END
    PORT
      LAYER met5 ;
        RECT 5.280 1764.330 2914.340 1767.430 ;
    END
    PORT
      LAYER met5 ;
        RECT 5.280 1839.330 2914.340 1842.430 ;
    END
    PORT
      LAYER met5 ;
        RECT 5.280 1914.330 2914.340 1917.430 ;
    END
    PORT
      LAYER met5 ;
        RECT 5.280 1989.330 2914.340 1992.430 ;
    END
    PORT
      LAYER met5 ;
        RECT 5.280 2064.330 2914.340 2067.430 ;
    END
    PORT
      LAYER met5 ;
        RECT 5.280 2139.330 2914.340 2142.430 ;
    END
    PORT
      LAYER met5 ;
        RECT 5.280 2214.330 2914.340 2217.430 ;
    END
    PORT
      LAYER met5 ;
        RECT 5.280 2289.330 2914.340 2292.430 ;
    END
    PORT
      LAYER met5 ;
        RECT 5.280 2364.330 2914.340 2367.430 ;
    END
    PORT
      LAYER met5 ;
        RECT 5.280 2439.330 2914.340 2442.430 ;
    END
    PORT
      LAYER met5 ;
        RECT 5.280 2514.330 2914.340 2517.430 ;
    END
    PORT
      LAYER met5 ;
        RECT 5.280 2589.330 2914.340 2592.430 ;
    END
    PORT
      LAYER met5 ;
        RECT 5.280 2664.330 2914.340 2667.430 ;
    END
    PORT
      LAYER met5 ;
        RECT 5.280 2739.330 2914.340 2742.430 ;
    END
    PORT
      LAYER met5 ;
        RECT 5.280 2814.330 2914.340 2817.430 ;
    END
    PORT
      LAYER met5 ;
        RECT 5.280 2889.330 2914.340 2892.430 ;
    END
    PORT
      LAYER met5 ;
        RECT 5.280 2964.330 2914.340 2967.430 ;
    END
    PORT
      LAYER met5 ;
        RECT 5.280 3039.330 2914.340 3042.430 ;
    END
    PORT
      LAYER met5 ;
        RECT 5.280 3114.330 2914.340 3117.430 ;
    END
    PORT
      LAYER met5 ;
        RECT 5.280 3189.330 2914.340 3192.430 ;
    END
    PORT
      LAYER met5 ;
        RECT 5.280 3264.330 2914.340 3267.430 ;
    END
    PORT
      LAYER met5 ;
        RECT 5.280 3339.330 2914.340 3342.430 ;
    END
    PORT
      LAYER met5 ;
        RECT 5.280 3414.330 2914.340 3417.430 ;
    END
    PORT
      LAYER met5 ;
        RECT 5.280 3489.330 2914.340 3492.430 ;
    END
  END vssd1
  OBS
      LAYER nwell ;
        RECT 5.330 10.760 2914.290 3508.920 ;
      LAYER li1 ;
        RECT 5.520 10.795 2914.100 3508.885 ;
      LAYER met1 ;
        RECT 5.520 0.380 2914.100 3509.040 ;
      LAYER met2 ;
        RECT 6.080 3515.720 96.410 3516.690 ;
        RECT 97.250 3515.720 2905.530 3516.690 ;
        RECT 6.080 4.280 2905.530 3515.720 ;
        RECT 6.080 0.350 212.330 4.280 ;
        RECT 213.170 0.350 215.550 4.280 ;
        RECT 216.390 0.350 2418.030 4.280 ;
        RECT 2418.870 0.350 2646.650 4.280 ;
        RECT 2647.490 0.350 2649.870 4.280 ;
        RECT 2650.710 0.350 2653.090 4.280 ;
        RECT 2653.930 0.350 2905.530 4.280 ;
      LAYER met3 ;
        RECT 4.000 3336.440 2905.510 3508.965 ;
        RECT 4.400 3335.040 2905.510 3336.440 ;
        RECT 4.000 3214.040 2905.510 3335.040 ;
        RECT 4.400 3212.640 2905.510 3214.040 ;
        RECT 4.000 3159.640 2905.510 3212.640 ;
        RECT 4.400 3158.240 2905.510 3159.640 ;
        RECT 4.000 3149.440 2905.510 3158.240 ;
        RECT 4.400 3148.040 2905.510 3149.440 ;
        RECT 4.000 3122.240 2905.510 3148.040 ;
        RECT 4.400 3120.840 2905.510 3122.240 ;
        RECT 4.000 3118.840 2905.510 3120.840 ;
        RECT 4.400 3117.440 2905.510 3118.840 ;
        RECT 4.000 3078.040 2905.510 3117.440 ;
        RECT 4.400 3076.640 2905.510 3078.040 ;
        RECT 4.000 2962.440 2905.510 3076.640 ;
        RECT 4.400 2961.040 2905.510 2962.440 ;
        RECT 4.000 2959.040 2905.510 2961.040 ;
        RECT 4.400 2957.640 2905.510 2959.040 ;
        RECT 4.000 2942.040 2905.510 2957.640 ;
        RECT 4.400 2940.640 2905.510 2942.040 ;
        RECT 4.000 2921.640 2905.510 2940.640 ;
        RECT 4.400 2920.240 2905.510 2921.640 ;
        RECT 4.000 2894.440 2905.510 2920.240 ;
        RECT 4.400 2893.040 2905.510 2894.440 ;
        RECT 4.000 2857.040 2905.510 2893.040 ;
        RECT 4.400 2855.640 2905.510 2857.040 ;
        RECT 4.000 2840.040 2905.510 2855.640 ;
        RECT 4.400 2838.640 2905.510 2840.040 ;
        RECT 4.000 2785.640 2905.510 2838.640 ;
        RECT 4.400 2784.240 2905.510 2785.640 ;
        RECT 4.000 2772.040 2905.510 2784.240 ;
        RECT 4.400 2770.640 2905.510 2772.040 ;
        RECT 4.000 2697.240 2905.510 2770.640 ;
        RECT 4.400 2695.840 2905.510 2697.240 ;
        RECT 4.000 2666.640 2905.510 2695.840 ;
        RECT 4.400 2665.240 2905.510 2666.640 ;
        RECT 4.000 2649.640 2905.510 2665.240 ;
        RECT 4.400 2648.240 2905.510 2649.640 ;
        RECT 4.000 2571.440 2905.510 2648.240 ;
        RECT 4.400 2570.040 2905.510 2571.440 ;
        RECT 4.000 2493.240 2905.510 2570.040 ;
        RECT 4.400 2491.840 2905.510 2493.240 ;
        RECT 4.000 2469.440 2905.510 2491.840 ;
        RECT 4.400 2468.040 2905.510 2469.440 ;
        RECT 4.000 2459.240 2905.510 2468.040 ;
        RECT 4.400 2457.840 2905.510 2459.240 ;
        RECT 4.000 2442.240 2905.510 2457.840 ;
        RECT 4.400 2440.840 2905.510 2442.240 ;
        RECT 4.000 2418.440 2905.510 2440.840 ;
        RECT 4.400 2417.040 2905.510 2418.440 ;
        RECT 4.000 2245.040 2905.510 2417.040 ;
        RECT 4.400 2243.640 2905.510 2245.040 ;
        RECT 4.000 2221.240 2905.510 2243.640 ;
        RECT 4.400 2219.840 2905.510 2221.240 ;
        RECT 4.000 2214.440 2905.510 2219.840 ;
        RECT 4.400 2213.040 2905.510 2214.440 ;
        RECT 4.000 2102.240 2905.510 2213.040 ;
        RECT 4.400 2100.840 2905.510 2102.240 ;
        RECT 4.000 2098.840 2905.510 2100.840 ;
        RECT 4.400 2097.440 2905.510 2098.840 ;
        RECT 4.000 2058.040 2905.510 2097.440 ;
        RECT 4.400 2056.640 2905.510 2058.040 ;
        RECT 4.000 2017.240 2905.510 2056.640 ;
        RECT 4.400 2015.840 2905.510 2017.240 ;
        RECT 4.000 2010.440 2905.510 2015.840 ;
        RECT 4.400 2009.040 2905.510 2010.440 ;
        RECT 4.000 1990.040 2905.510 2009.040 ;
        RECT 4.400 1988.640 2905.510 1990.040 ;
        RECT 4.000 1959.440 2905.510 1988.640 ;
        RECT 4.400 1958.040 2905.510 1959.440 ;
        RECT 4.000 1820.040 2905.510 1958.040 ;
        RECT 4.400 1818.640 2905.510 1820.040 ;
        RECT 4.000 1813.240 2905.510 1818.640 ;
        RECT 4.400 1811.840 2905.510 1813.240 ;
        RECT 4.000 1789.440 2905.510 1811.840 ;
        RECT 4.400 1788.040 2905.510 1789.440 ;
        RECT 4.000 1775.840 2905.510 1788.040 ;
        RECT 4.400 1774.440 2905.510 1775.840 ;
        RECT 4.000 1762.240 2905.510 1774.440 ;
        RECT 4.400 1760.840 2905.510 1762.240 ;
        RECT 4.000 1724.840 2905.510 1760.840 ;
        RECT 4.400 1723.440 2905.510 1724.840 ;
        RECT 4.000 1653.440 2905.510 1723.440 ;
        RECT 4.400 1652.040 2905.510 1653.440 ;
        RECT 4.000 1565.040 2905.510 1652.040 ;
        RECT 4.400 1563.640 2905.510 1565.040 ;
        RECT 4.000 1534.440 2905.510 1563.640 ;
        RECT 4.400 1533.040 2905.510 1534.440 ;
        RECT 4.000 1435.840 2905.510 1533.040 ;
        RECT 4.400 1434.440 2905.510 1435.840 ;
        RECT 4.000 1391.640 2905.510 1434.440 ;
        RECT 4.400 1390.240 2905.510 1391.640 ;
        RECT 4.000 1388.240 2905.510 1390.240 ;
        RECT 4.400 1386.840 2905.510 1388.240 ;
        RECT 4.000 1374.640 2905.510 1386.840 ;
        RECT 4.400 1373.240 2905.510 1374.640 ;
        RECT 4.000 1340.640 2905.510 1373.240 ;
        RECT 4.400 1339.240 2905.510 1340.640 ;
        RECT 4.000 1337.240 2905.510 1339.240 ;
        RECT 4.400 1335.840 2905.510 1337.240 ;
        RECT 4.000 1310.040 2905.510 1335.840 ;
        RECT 4.400 1308.640 2905.510 1310.040 ;
        RECT 4.000 1296.440 2905.510 1308.640 ;
        RECT 4.400 1295.040 2905.510 1296.440 ;
        RECT 4.000 1252.240 2905.510 1295.040 ;
        RECT 4.400 1250.840 2905.510 1252.240 ;
        RECT 4.000 1228.440 2905.510 1250.840 ;
        RECT 4.400 1227.040 2905.510 1228.440 ;
        RECT 4.000 1143.440 2905.510 1227.040 ;
        RECT 4.400 1142.040 2905.510 1143.440 ;
        RECT 4.000 1112.840 2905.510 1142.040 ;
        RECT 4.400 1111.440 2905.510 1112.840 ;
        RECT 4.000 1082.240 2905.510 1111.440 ;
        RECT 4.400 1080.840 2905.510 1082.240 ;
        RECT 4.000 1058.440 2905.510 1080.840 ;
        RECT 4.400 1057.040 2905.510 1058.440 ;
        RECT 4.000 1000.640 2905.510 1057.040 ;
        RECT 4.400 999.240 2905.510 1000.640 ;
        RECT 4.000 956.440 2905.510 999.240 ;
        RECT 4.400 955.040 2905.510 956.440 ;
        RECT 4.000 932.640 2905.510 955.040 ;
        RECT 4.400 931.240 2905.510 932.640 ;
        RECT 4.000 885.040 2905.510 931.240 ;
        RECT 4.400 883.640 2905.510 885.040 ;
        RECT 4.000 881.640 2905.510 883.640 ;
        RECT 4.400 880.240 2905.510 881.640 ;
        RECT 4.000 874.840 2905.510 880.240 ;
        RECT 4.400 873.440 2905.510 874.840 ;
        RECT 4.000 854.440 2905.510 873.440 ;
        RECT 4.400 853.040 2905.510 854.440 ;
        RECT 4.000 823.840 2905.510 853.040 ;
        RECT 4.400 822.440 2905.510 823.840 ;
        RECT 4.000 721.840 2905.510 822.440 ;
        RECT 4.400 720.440 2905.510 721.840 ;
        RECT 4.000 657.240 2905.510 720.440 ;
        RECT 4.400 655.840 2905.510 657.240 ;
        RECT 4.000 630.040 2905.510 655.840 ;
        RECT 4.400 628.640 2905.510 630.040 ;
        RECT 4.000 616.440 2905.510 628.640 ;
        RECT 4.400 615.040 2905.510 616.440 ;
        RECT 4.000 602.840 2905.510 615.040 ;
        RECT 4.400 601.440 2905.510 602.840 ;
        RECT 4.000 599.440 2905.510 601.440 ;
        RECT 4.400 598.040 2905.510 599.440 ;
        RECT 4.000 456.640 2905.510 598.040 ;
        RECT 4.400 455.240 2905.510 456.640 ;
        RECT 4.000 432.840 2905.510 455.240 ;
        RECT 4.400 431.440 2905.510 432.840 ;
        RECT 4.000 402.240 2905.510 431.440 ;
        RECT 4.400 400.840 2905.510 402.240 ;
        RECT 4.000 317.240 2905.510 400.840 ;
        RECT 4.400 315.840 2905.510 317.240 ;
        RECT 4.000 283.240 2905.510 315.840 ;
        RECT 4.400 281.840 2905.510 283.240 ;
        RECT 4.000 269.640 2905.510 281.840 ;
        RECT 4.400 268.240 2905.510 269.640 ;
        RECT 4.000 120.040 2905.510 268.240 ;
        RECT 4.400 118.640 2905.510 120.040 ;
        RECT 4.000 116.640 2905.510 118.640 ;
        RECT 4.400 115.240 2905.510 116.640 ;
        RECT 4.000 113.240 2905.510 115.240 ;
        RECT 4.400 111.840 2905.510 113.240 ;
        RECT 4.000 52.040 2905.510 111.840 ;
        RECT 4.400 50.640 2905.510 52.040 ;
        RECT 4.000 10.715 2905.510 50.640 ;
      LAYER met4 ;
        RECT 60.095 25.200 108.570 3447.760 ;
        RECT 112.470 3350.025 127.170 3447.760 ;
        RECT 131.070 3350.025 183.570 3447.760 ;
        RECT 187.470 3357.505 202.170 3447.760 ;
        RECT 206.070 3357.505 277.170 3447.760 ;
        RECT 281.070 3357.505 333.570 3447.760 ;
        RECT 337.470 3357.505 483.570 3447.760 ;
        RECT 487.470 3357.505 502.170 3447.760 ;
        RECT 506.070 3357.505 558.570 3447.760 ;
        RECT 562.470 3357.505 708.570 3447.760 ;
        RECT 712.470 3357.505 727.170 3447.760 ;
        RECT 187.470 3350.705 727.170 3357.505 ;
        RECT 731.070 3354.140 783.570 3447.760 ;
        RECT 787.470 3354.140 802.170 3447.760 ;
        RECT 731.070 3350.705 802.170 3354.140 ;
        RECT 806.070 3354.140 858.570 3447.760 ;
        RECT 862.470 3354.140 877.170 3447.760 ;
        RECT 806.070 3350.705 877.170 3354.140 ;
        RECT 881.070 3357.505 933.570 3447.760 ;
        RECT 937.470 3357.505 1008.570 3447.760 ;
        RECT 1012.470 3357.505 1158.570 3447.760 ;
        RECT 1162.470 3357.505 1233.570 3447.760 ;
        RECT 1237.470 3357.505 1252.170 3447.760 ;
        RECT 1256.070 3363.365 1383.570 3447.760 ;
        RECT 1387.470 3363.365 1402.170 3447.760 ;
        RECT 1406.070 3363.365 1608.570 3447.760 ;
        RECT 1612.470 3363.365 1627.170 3447.760 ;
        RECT 1631.070 3363.365 1702.170 3447.760 ;
        RECT 1256.070 3357.505 1702.170 3363.365 ;
        RECT 1706.070 3357.505 1852.170 3447.760 ;
        RECT 1856.070 3357.505 1927.170 3447.760 ;
        RECT 1931.070 3358.865 2077.170 3447.760 ;
        RECT 2081.070 3447.665 2152.170 3447.760 ;
        RECT 2156.070 3447.665 2208.570 3447.760 ;
        RECT 2081.070 3358.865 2208.570 3447.665 ;
        RECT 2212.470 3358.865 2227.170 3447.760 ;
        RECT 1931.070 3357.505 2227.170 3358.865 ;
        RECT 881.070 3350.705 2227.170 3357.505 ;
        RECT 187.470 3350.445 2227.170 3350.705 ;
        RECT 2231.070 3363.180 2283.570 3447.760 ;
        RECT 2287.470 3363.180 2302.170 3447.760 ;
        RECT 2306.070 3363.180 2358.570 3447.760 ;
        RECT 2362.470 3363.180 2377.170 3447.760 ;
        RECT 2381.070 3363.180 2433.570 3447.760 ;
        RECT 2437.470 3363.180 2452.170 3447.760 ;
        RECT 2456.070 3363.180 2508.570 3447.760 ;
        RECT 2512.470 3363.180 2527.170 3447.760 ;
        RECT 2531.070 3363.180 2583.570 3447.760 ;
        RECT 2587.470 3363.180 2602.170 3447.760 ;
        RECT 2606.070 3363.180 2658.570 3447.760 ;
        RECT 2662.470 3363.180 2677.170 3447.760 ;
        RECT 2681.070 3363.180 2733.570 3447.760 ;
        RECT 2737.470 3363.180 2752.170 3447.760 ;
        RECT 2756.070 3363.180 2778.080 3447.760 ;
        RECT 2231.070 3350.445 2778.080 3363.180 ;
        RECT 187.470 3350.025 2778.080 3350.445 ;
        RECT 112.470 137.795 2778.080 3350.025 ;
        RECT 112.470 135.755 1402.170 137.795 ;
        RECT 112.470 131.675 727.170 135.755 ;
        RECT 112.470 127.795 277.170 131.675 ;
        RECT 112.470 25.200 127.170 127.795 ;
        RECT 131.070 25.200 183.570 127.795 ;
        RECT 187.470 126.400 277.170 127.795 ;
        RECT 187.470 25.200 202.170 126.400 ;
        RECT 206.070 85.340 277.170 126.400 ;
        RECT 206.070 25.200 258.570 85.340 ;
        RECT 262.470 25.200 277.170 85.340 ;
        RECT 281.070 25.200 333.570 131.675 ;
        RECT 337.470 25.200 352.170 131.675 ;
        RECT 356.070 25.200 408.570 131.675 ;
        RECT 412.470 25.200 427.170 131.675 ;
        RECT 431.070 25.200 483.570 131.675 ;
        RECT 487.470 25.200 502.170 131.675 ;
        RECT 506.070 25.200 558.570 131.675 ;
        RECT 562.470 25.200 577.170 131.675 ;
        RECT 581.070 25.200 633.570 131.675 ;
        RECT 637.470 25.200 652.170 131.675 ;
        RECT 656.070 25.200 708.570 131.675 ;
        RECT 712.470 25.200 727.170 131.675 ;
        RECT 731.070 110.535 858.570 135.755 ;
        RECT 731.070 25.200 783.570 110.535 ;
        RECT 787.470 25.200 802.170 110.535 ;
        RECT 806.070 25.200 858.570 110.535 ;
        RECT 862.470 25.200 877.170 135.755 ;
        RECT 881.070 131.675 1402.170 135.755 ;
        RECT 881.070 25.200 933.570 131.675 ;
        RECT 937.470 85.340 1008.570 131.675 ;
        RECT 937.470 25.200 952.170 85.340 ;
        RECT 956.070 25.200 1008.570 85.340 ;
        RECT 1012.470 85.340 1102.170 131.675 ;
        RECT 1012.470 25.200 1027.170 85.340 ;
        RECT 1031.070 25.200 1083.570 85.340 ;
        RECT 1087.470 25.200 1102.170 85.340 ;
        RECT 1106.070 25.200 1158.570 131.675 ;
        RECT 1162.470 85.340 1233.570 131.675 ;
        RECT 1162.470 25.200 1177.170 85.340 ;
        RECT 1181.070 25.200 1233.570 85.340 ;
        RECT 1237.470 25.200 1252.170 131.675 ;
        RECT 1256.070 85.340 1327.170 131.675 ;
        RECT 1256.070 25.200 1308.570 85.340 ;
        RECT 1312.470 25.200 1327.170 85.340 ;
        RECT 1331.070 25.200 1383.570 131.675 ;
        RECT 1387.470 25.200 1402.170 131.675 ;
        RECT 1406.070 133.715 2778.080 137.795 ;
        RECT 1406.070 131.675 2227.170 133.715 ;
        RECT 1406.070 89.455 1608.570 131.675 ;
        RECT 1406.070 25.200 1458.570 89.455 ;
        RECT 1462.470 25.200 1477.170 89.455 ;
        RECT 1481.070 25.200 1533.570 89.455 ;
        RECT 1537.470 79.900 1608.570 89.455 ;
        RECT 1537.470 25.200 1552.170 79.900 ;
        RECT 1556.070 25.200 1608.570 79.900 ;
        RECT 1612.470 25.200 1627.170 131.675 ;
        RECT 1631.070 85.340 1702.170 131.675 ;
        RECT 1631.070 25.200 1683.570 85.340 ;
        RECT 1687.470 25.200 1702.170 85.340 ;
        RECT 1706.070 85.340 1777.170 131.675 ;
        RECT 1706.070 25.200 1758.570 85.340 ;
        RECT 1762.470 25.200 1777.170 85.340 ;
        RECT 1781.070 25.200 1833.570 131.675 ;
        RECT 1837.470 25.200 1852.170 131.675 ;
        RECT 1856.070 85.340 1927.170 131.675 ;
        RECT 1856.070 25.200 1908.570 85.340 ;
        RECT 1912.470 25.200 1927.170 85.340 ;
        RECT 1931.070 25.200 1983.570 131.675 ;
        RECT 1987.470 25.200 2002.170 131.675 ;
        RECT 2006.070 25.200 2058.570 131.675 ;
        RECT 2062.470 25.200 2077.170 131.675 ;
        RECT 2081.070 84.015 2227.170 131.675 ;
        RECT 2081.070 79.900 2152.170 84.015 ;
        RECT 2081.070 25.200 2133.570 79.900 ;
        RECT 2137.470 25.200 2152.170 79.900 ;
        RECT 2156.070 25.200 2208.570 84.015 ;
        RECT 2212.470 25.200 2227.170 84.015 ;
        RECT 2231.070 125.760 2778.080 133.715 ;
        RECT 2231.070 25.200 2283.570 125.760 ;
        RECT 2287.470 125.740 2358.570 125.760 ;
        RECT 2287.470 25.200 2302.170 125.740 ;
        RECT 2306.070 25.200 2358.570 125.740 ;
        RECT 2362.470 125.740 2733.570 125.760 ;
        RECT 2362.470 25.200 2377.170 125.740 ;
        RECT 2381.070 25.200 2658.570 125.740 ;
        RECT 2662.470 25.200 2733.570 125.740 ;
        RECT 2737.470 125.740 2778.080 125.760 ;
        RECT 2737.470 25.200 2752.170 125.740 ;
        RECT 2756.070 25.200 2778.080 125.740 ;
      LAYER met5 ;
        RECT 2217.620 3287.630 2778.080 3327.880 ;
        RECT 2217.620 3269.030 2778.080 3281.330 ;
        RECT 2217.620 3212.630 2778.080 3262.730 ;
        RECT 2217.620 3194.030 2778.080 3206.330 ;
        RECT 2217.620 3137.630 2778.080 3187.730 ;
        RECT 2217.620 3119.030 2778.080 3131.330 ;
        RECT 2217.620 3062.630 2778.080 3112.730 ;
        RECT 2217.620 3044.030 2778.080 3056.330 ;
        RECT 2217.620 2987.630 2778.080 3037.730 ;
        RECT 2217.620 2969.030 2778.080 2981.330 ;
        RECT 2217.620 2894.030 2778.080 2962.730 ;
        RECT 2217.620 2837.630 2778.080 2887.730 ;
        RECT 2217.620 2819.030 2778.080 2831.330 ;
        RECT 2217.620 2762.630 2778.080 2812.730 ;
        RECT 2217.620 2744.030 2778.080 2756.330 ;
        RECT 2217.620 2687.630 2778.080 2737.730 ;
        RECT 2217.620 2669.030 2778.080 2681.330 ;
        RECT 2217.620 2612.630 2778.080 2662.730 ;
        RECT 2217.620 2594.030 2778.080 2606.330 ;
        RECT 2217.620 2537.630 2778.080 2587.730 ;
        RECT 2217.620 2519.030 2778.080 2531.330 ;
        RECT 2217.620 2444.030 2778.080 2512.730 ;
        RECT 2217.620 2369.030 2778.080 2437.730 ;
        RECT 2217.620 2312.630 2778.080 2362.730 ;
        RECT 2217.620 2294.030 2778.080 2306.330 ;
        RECT 2217.620 2237.630 2778.080 2287.730 ;
        RECT 2217.620 2219.030 2778.080 2231.330 ;
        RECT 2217.620 2162.630 2778.080 2212.730 ;
        RECT 2217.620 2144.030 2778.080 2156.330 ;
        RECT 2217.620 2087.630 2778.080 2137.730 ;
        RECT 2217.620 2069.030 2778.080 2081.330 ;
        RECT 2217.620 1994.030 2778.080 2062.730 ;
        RECT 2217.620 1919.030 2778.080 1987.730 ;
        RECT 2217.620 1862.630 2778.080 1912.730 ;
        RECT 2217.620 1844.030 2778.080 1856.330 ;
        RECT 2217.620 1787.630 2778.080 1837.730 ;
        RECT 2217.620 1769.030 2778.080 1781.330 ;
        RECT 2217.620 1712.630 2778.080 1762.730 ;
        RECT 2217.620 1694.030 2778.080 1706.330 ;
        RECT 2217.620 1637.630 2778.080 1687.730 ;
        RECT 2217.620 1619.030 2778.080 1631.330 ;
        RECT 2217.620 1544.030 2778.080 1612.730 ;
        RECT 2217.620 1469.030 2778.080 1537.730 ;
        RECT 2217.620 1412.630 2778.080 1462.730 ;
        RECT 2217.620 1394.030 2778.080 1406.330 ;
        RECT 2217.620 1337.630 2778.080 1387.730 ;
        RECT 2217.620 1319.030 2778.080 1331.330 ;
        RECT 2217.620 1262.630 2778.080 1312.730 ;
        RECT 2217.620 1244.030 2778.080 1256.330 ;
        RECT 2217.620 1187.630 2778.080 1237.730 ;
        RECT 2217.620 1169.030 2778.080 1181.330 ;
        RECT 2217.620 1094.030 2778.080 1162.730 ;
        RECT 2217.620 1019.030 2778.080 1087.730 ;
        RECT 2217.620 962.630 2778.080 1012.730 ;
        RECT 2217.620 944.030 2778.080 956.330 ;
        RECT 2217.620 887.630 2778.080 937.730 ;
        RECT 2217.620 869.030 2778.080 881.330 ;
        RECT 2217.620 812.630 2778.080 862.730 ;
        RECT 2217.620 794.030 2778.080 806.330 ;
        RECT 2217.620 737.630 2778.080 787.730 ;
        RECT 2217.620 719.030 2778.080 731.330 ;
        RECT 2217.620 662.630 2778.080 712.730 ;
        RECT 2217.620 644.030 2778.080 656.330 ;
        RECT 2217.620 569.030 2778.080 637.730 ;
        RECT 2217.620 512.630 2778.080 562.730 ;
        RECT 2217.620 494.030 2778.080 506.330 ;
        RECT 2217.620 437.630 2778.080 487.730 ;
        RECT 2217.620 419.030 2778.080 431.330 ;
        RECT 2217.620 362.630 2778.080 412.730 ;
        RECT 2217.620 344.030 2778.080 356.330 ;
        RECT 2217.620 287.630 2778.080 337.730 ;
        RECT 2217.620 269.030 2778.080 281.330 ;
        RECT 2217.620 212.630 2778.080 262.730 ;
        RECT 2217.620 194.030 2778.080 206.330 ;
        RECT 2217.620 161.040 2778.080 187.730 ;
  END
END efpga_core
END LIBRARY

